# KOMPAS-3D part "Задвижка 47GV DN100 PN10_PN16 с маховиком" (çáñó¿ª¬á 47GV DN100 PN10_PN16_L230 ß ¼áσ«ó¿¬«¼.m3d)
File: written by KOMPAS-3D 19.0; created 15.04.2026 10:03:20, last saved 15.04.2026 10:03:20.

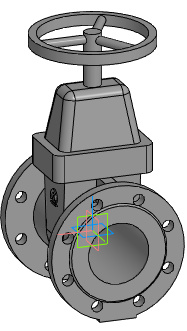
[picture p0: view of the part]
Document properties: Автор: Евгений; Полное имя файла: Z:\3.Личные\kachalov\3d для проектировщиков\2.1 Тип 47GV, 47GV.Z\Задвижка 47GV_DN40-DN600\stp_Задвижка 47GV\Задвижка 47GV DN100 PN10_PN16_L230 с маховиком.m3d

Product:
- Part/product: Задвижка 47GV DN100 PN10_PN16 с маховиком

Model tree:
1. Операция без истории:1  (labels: Задвижка 47GV DN100 PN10_PN16 с маховиком)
